# Copyright 2023 ETH Zurich and University of Bologna.
# Solderpad Hardware License, Version 0.51, see LICENSE for details.
# SPDX-License-Identifier: SHL-0.51

# LEF for the sg13g2_iocell library
# Automatically generated by gds2lef_sg13g2.py
# Extracted from sg13g2_iocell.gds

# Authors:
# - Thomas Benz <tbenz@iis.ee.ethz.ch>

VERSION 5.7 ;
BUSBITCHARS "<>" ;
DIVIDERCHAR "/" ;

PROPERTYDEFINITIONS
  MACRO CatenaDesignType STRING ;
END PROPERTYDEFINITIONS

SITE  IOSite
  CLASS    PAD ;
  SYMMETRY R90 ;
  SIZE	1.00 BY 310.00 ;
END  IOSite

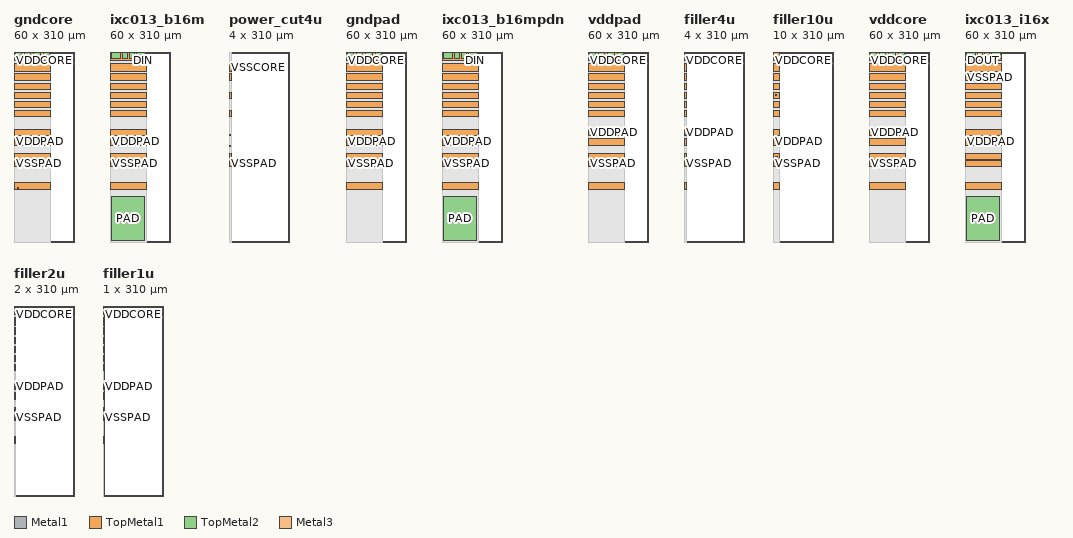
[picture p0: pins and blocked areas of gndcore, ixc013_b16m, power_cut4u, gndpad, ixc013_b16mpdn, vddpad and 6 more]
MACRO gndcore
  CLASS PAD ;
  ORIGIN 0 0 ;
  FOREIGN gndcore 0 0 ;
  SIZE 60 BY 310 ;
  SYMMETRY X Y R90 ;
  SITE IOSite ;
  PIN VSSPAD
    DIRECTION INOUT ;
    USE GROUND ;
    PORT
      LAYER Metal1 ;
        RECT 5.77 87.69 7.6 88.64 ;
    END
    PORT
      LAYER TopMetal1 ;
        RECT 0.0 122.745 60.0 132.745 ;
        RECT 0.0 134.39 60.0 144.39 ;
        RECT 0.0 204.15 60.0 214.15 ;
        RECT 0.0 234.15 60.0 244.15 ;
        RECT 0.0 264.15 60.0 274.15 ;
    END
  END VSSPAD
  PIN VDDPAD
    DIRECTION INOUT ;
    USE POWER ;
    PORT
      LAYER TopMetal1 ;
        RECT 0.0 86.405 60.0 96.405 ;
        RECT 0.0 219.15 60.0 229.15 ;
        RECT 0.0 249.15 60.0 259.15 ;
        RECT 0.0 158.15 60.0 168.65 ;
        RECT 0.0 173.65 60.0 184.15 ;
    END
  END VDDPAD
  PIN VDDCORE
    DIRECTION INOUT ;
    USE POWER ;
    PORT
      LAYER TopMetal1 ;
        RECT 0.0 296.15 60.0 309.15 ;
    END
    PORT
      LAYER TopMetal2 ;
        RECT 47.5 301.39 57.5 310.0 ;
        RECT 2.5 301.39 12.5 310.0 ;
    END
  END VDDCORE
  PIN VSSCORE
    DIRECTION INOUT ;
    USE GROUND ;
    PORT
      LAYER TopMetal1 ;
        RECT 0.0 278.15 60.0 291.15 ;
    END
    PORT
      LAYER TopMetal2 ;
        RECT 32.5 301.39 42.5 310.0 ;
        RECT 17.5 301.39 27.5 310.0 ;
    END
  END VSSCORE
  OBS
    LAYER Metal1 ;
      RECT 0 0 60 310 ;
    LAYER Metal2 ;
      RECT 0 0 60 310 ;
    LAYER Metal3 ;
      RECT 0 0 60 310 ;
    LAYER Metal4 ;
      RECT 0 0 60 310 ;
    LAYER Metal5 ;
      RECT 0 0 60 310 ;
    LAYER TopMetal1 ;
      RECT 0 0 60 310 ;
    LAYER TopMetal2 ;
      RECT 0 0 60 310 ;
  END
END gndcore

MACRO ixc013_b16m
  CLASS PAD ;
  ORIGIN 0 0 ;
  FOREIGN ixc013_b16m 0 0 ;
  SIZE 60 BY 310 ;
  SYMMETRY X Y R90 ;
  SITE IOSite ;
  PIN DOUT
    DIRECTION OUTPUT ;
    USE SIGNAL ;
    PORT
      LAYER Metal3 ;
        RECT 7.865 309.0 8.865 310.0 ;
    END
  END DOUT
  PIN OEN
    DIRECTION INPUT ;
    USE SIGNAL ;
    PORT
      LAYER Metal3 ;
        RECT 54.745 309.0 55.745 310.0 ;
    END
  END OEN
  PIN DIN
    DIRECTION INPUT ;
    USE SIGNAL ;
    PORT
      LAYER Metal3 ;
        RECT 52.745 309.0 53.745 310.0 ;
    END
  END DIN
  PIN VDDPAD
    DIRECTION INOUT ;
    USE POWER ;
    PORT
      LAYER TopMetal1 ;
        RECT 0.0 86.405 60.0 96.405 ;
        RECT 0.0 219.15 60.0 229.15 ;
        RECT 0.0 249.15 60.0 259.15 ;
        RECT 0.0 158.15 60.0 168.65 ;
        RECT 0.0 173.65 60.0 184.15 ;
    END
    PORT
      LAYER TopMetal2 ;
        RECT 1.96 298.75 16.96 310.0 ;
        RECT 32.085 298.75 40.085 310.0 ;
    END
  END VDDPAD
  PIN VSSPAD
    DIRECTION INOUT ;
    USE GROUND ;
    PORT
      LAYER TopMetal1 ;
        RECT 0.0 122.745 60.0 132.745 ;
        RECT 0.0 134.39 60.0 144.39 ;
        RECT 0.0 204.15 60.0 214.15 ;
        RECT 0.0 234.15 60.0 244.15 ;
        RECT 0.0 264.15 60.0 274.15 ;
    END
    PORT
      LAYER TopMetal2 ;
        RECT 20.085 298.75 28.085 310.0 ;
        RECT 43.21 298.75 58.21 310.0 ;
    END
  END VSSPAD
  PIN VDDCORE
    DIRECTION INOUT ;
    USE POWER ;
    PORT
      LAYER TopMetal1 ;
        RECT 0.0 296.15 60.0 309.15 ;
    END
  END VDDCORE
  PIN VSSCORE
    DIRECTION INOUT ;
    USE GROUND ;
    PORT
      LAYER TopMetal1 ;
        RECT 0.0 278.15 60.0 291.15 ;
    END
  END VSSCORE
  PIN PAD
    DIRECTION INOUT ;
    USE SIGNAL ;
    PORT
      LAYER TopMetal2 ;
        RECT 2.9 2.535 57.1 73.735 ;
    END
  END PAD
  OBS
    LAYER Metal1 ;
      RECT 0 0 60 310 ;
    LAYER Metal2 ;
      RECT 0 0 60 310 ;
    LAYER Metal3 ;
      RECT 0 0 60 310 ;
    LAYER Metal4 ;
      RECT 0 0 60 310 ;
    LAYER Metal5 ;
      RECT 0 0 60 310 ;
    LAYER TopMetal1 ;
      RECT 0 0 60 310 ;
    LAYER TopMetal2 ;
      RECT 0 0 60 310 ;
  END
END ixc013_b16m

MACRO power_cut4u
  CLASS PAD ;
  ORIGIN 0 0 ;
  FOREIGN power_cut4u 0 0 ;
  SIZE 4 BY 310 ;
  SYMMETRY X Y R90 ;
  SITE IOSite ;
  PIN VSSPAD
    DIRECTION INOUT ;
    USE GROUND ;
    PORT
      LAYER Metal1 ;
        RECT 1.42 173.42 2.58 174.59 ;
        RECT 1.28 155.28 2.72 157.2 ;
    END
    PORT
      LAYER TopMetal1 ;
        RECT 0.0 122.745 4.0 132.745 ;
        RECT 0.0 134.39 4.0 144.39 ;
        RECT 0.0 204.15 4.0 214.15 ;
        RECT 0.0 234.15 4.0 244.15 ;
        RECT 0.0 264.15 4.0 274.15 ;
    END
  END VSSPAD
  PIN VSSCORE
    DIRECTION INOUT ;
    USE GROUND ;
    PORT
      LAYER TopMetal1 ;
        RECT 0.0 278.15 4.0 291.15 ;
    END
  END VSSCORE
  OBS
    LAYER Metal1 ;
      RECT 0 0 4 310 ;
    LAYER Metal2 ;
      RECT 0 0 4 310 ;
    LAYER Metal3 ;
      RECT 0 0 4 310 ;
    LAYER Metal4 ;
      RECT 0 0 4 310 ;
    LAYER Metal5 ;
      RECT 0 0 4 310 ;
    LAYER TopMetal1 ;
      RECT 0 0 4 310 ;
    LAYER TopMetal2 ;
      RECT 0 0 4 310 ;
  END
END power_cut4u

MACRO gndpad
  CLASS PAD ;
  ORIGIN 0 0 ;
  FOREIGN gndpad 0 0 ;
  SIZE 60 BY 310 ;
  SYMMETRY X Y R90 ;
  SITE IOSite ;
  PIN VDDPAD
    DIRECTION INOUT ;
    USE POWER ;
    PORT
      LAYER TopMetal1 ;
        RECT 0.0 86.405 60.0 96.405 ;
        RECT 0.0 219.15 60.0 229.15 ;
        RECT 0.0 249.15 60.0 259.15 ;
        RECT 0.0 158.15 60.0 168.65 ;
        RECT 0.0 173.65 60.0 184.15 ;
    END
    PORT
      LAYER TopMetal2 ;
        RECT 47.5 301.39 57.5 310.0 ;
        RECT 2.5 301.39 12.5 310.0 ;
    END
  END VDDPAD
  PIN VSSPAD
    DIRECTION INOUT ;
    USE GROUND ;
    PORT
      LAYER TopMetal1 ;
        RECT 0.0 122.745 60.0 132.745 ;
        RECT 0.0 134.39 60.0 144.39 ;
        RECT 0.0 204.15 60.0 214.15 ;
        RECT 0.0 234.15 60.0 244.15 ;
        RECT 0.0 264.15 60.0 274.15 ;
    END
    PORT
      LAYER TopMetal2 ;
        RECT 32.5 301.39 42.5 310.0 ;
        RECT 17.5 301.39 27.5 310.0 ;
    END
  END VSSPAD
  PIN VDDCORE
    DIRECTION INOUT ;
    USE POWER ;
    PORT
      LAYER TopMetal1 ;
        RECT 0.0 296.15 60.0 309.15 ;
    END
  END VDDCORE
  PIN VSSCORE
    DIRECTION INOUT ;
    USE GROUND ;
    PORT
      LAYER TopMetal1 ;
        RECT 0.0 278.15 60.0 291.15 ;
    END
  END VSSCORE
  OBS
    LAYER Metal1 ;
      RECT 0 0 60 310 ;
    LAYER Metal2 ;
      RECT 0 0 60 310 ;
    LAYER Metal3 ;
      RECT 0 0 60 310 ;
    LAYER Metal4 ;
      RECT 0 0 60 310 ;
    LAYER Metal5 ;
      RECT 0 0 60 310 ;
    LAYER TopMetal1 ;
      RECT 0 0 60 310 ;
    LAYER TopMetal2 ;
      RECT 0 0 60 310 ;
  END
END gndpad

MACRO ixc013_b16mpdn
  CLASS PAD ;
  ORIGIN 0 0 ;
  FOREIGN ixc013_b16mpdn 0 0 ;
  SIZE 60 BY 310 ;
  SYMMETRY X Y R90 ;
  SITE IOSite ;
  PIN DOUT
    DIRECTION OUTPUT ;
    USE SIGNAL ;
    PORT
      LAYER Metal3 ;
        RECT 7.865 309.0 8.865 310.0 ;
    END
  END DOUT
  PIN OEN
    DIRECTION INPUT ;
    USE SIGNAL ;
    PORT
      LAYER Metal3 ;
        RECT 54.745 309.0 55.745 310.0 ;
    END
  END OEN
  PIN DIN
    DIRECTION INPUT ;
    USE SIGNAL ;
    PORT
      LAYER Metal3 ;
        RECT 52.745 309.0 53.745 310.0 ;
    END
  END DIN
  PIN VDDPAD
    DIRECTION INOUT ;
    USE POWER ;
    PORT
      LAYER TopMetal1 ;
        RECT 0.0 86.405 60.0 96.405 ;
        RECT 0.0 219.15 60.0 229.15 ;
        RECT 0.0 249.15 60.0 259.15 ;
        RECT 0.0 158.15 60.0 168.65 ;
        RECT 0.0 173.65 60.0 184.15 ;
    END
    PORT
      LAYER TopMetal2 ;
        RECT 1.96 298.75 16.96 310.0 ;
        RECT 32.085 298.75 40.085 310.0 ;
    END
  END VDDPAD
  PIN VSSPAD
    DIRECTION INOUT ;
    USE GROUND ;
    PORT
      LAYER TopMetal1 ;
        RECT 0.0 122.745 60.0 132.745 ;
        RECT 0.0 134.39 60.0 144.39 ;
        RECT 0.0 204.15 60.0 214.15 ;
        RECT 0.0 234.15 60.0 244.15 ;
        RECT 0.0 264.15 60.0 274.15 ;
    END
    PORT
      LAYER TopMetal2 ;
        RECT 20.085 298.75 28.085 310.0 ;
        RECT 43.21 298.75 58.21 310.0 ;
    END
  END VSSPAD
  PIN VDDCORE
    DIRECTION INOUT ;
    USE POWER ;
    PORT
      LAYER TopMetal1 ;
        RECT 0.0 296.15 60.0 309.15 ;
    END
  END VDDCORE
  PIN VSSCORE
    DIRECTION INOUT ;
    USE GROUND ;
    PORT
      LAYER TopMetal1 ;
        RECT 0.0 278.15 60.0 291.15 ;
    END
  END VSSCORE
  PIN PAD
    DIRECTION INOUT ;
    USE SIGNAL ;
    PORT
      LAYER TopMetal2 ;
        RECT 2.9 2.535 57.1 73.735 ;
    END
  END PAD
  OBS
    LAYER Metal1 ;
      RECT 0 0 60 310 ;
    LAYER Metal2 ;
      RECT 0 0 60 310 ;
    LAYER Metal3 ;
      RECT 0 0 60 310 ;
    LAYER Metal4 ;
      RECT 0 0 60 310 ;
    LAYER Metal5 ;
      RECT 0 0 60 310 ;
    LAYER TopMetal1 ;
      RECT 0 0 60 310 ;
    LAYER TopMetal2 ;
      RECT 0 0 60 310 ;
  END
END ixc013_b16mpdn

MACRO vddpad
  CLASS PAD ;
  ORIGIN 0 0 ;
  FOREIGN vddpad 0 0 ;
  SIZE 60 BY 310 ;
  SYMMETRY X Y R90 ;
  SITE IOSite ;
  PIN VDDPAD
    DIRECTION INOUT ;
    USE POWER ;
    PORT
      LAYER TopMetal1 ;
        RECT 0.0 86.405 60.0 96.405 ;
        RECT 0.0 219.15 60.0 229.15 ;
        RECT 0.0 249.15 60.0 259.15 ;
        RECT 0.0 173.65 60.0 184.15 ;
        RECT 0.0 158.15 60.0 168.65 ;
    END
    PORT
      LAYER TopMetal2 ;
        RECT 17.5 301.39 27.5 310.0 ;
        RECT 32.5 301.39 42.5 310.0 ;
    END
  END VDDPAD
  PIN VSSPAD
    DIRECTION INOUT ;
    USE GROUND ;
    PORT
      LAYER TopMetal1 ;
        RECT 0.0 122.745 60.0 132.745 ;
        RECT 0.0 134.39 60.0 144.39 ;
        RECT 0.0 204.15 60.0 214.15 ;
        RECT 0.0 234.15 60.0 244.15 ;
        RECT 0.0 264.15 60.0 274.15 ;
    END
    PORT
      LAYER TopMetal2 ;
        RECT 47.5 301.39 57.5 310.0 ;
        RECT 2.5 301.39 12.5 310.0 ;
    END
  END VSSPAD
  PIN VSSCORE
    DIRECTION INOUT ;
    USE GROUND ;
    PORT
      LAYER TopMetal1 ;
        RECT 0.0 278.15 60.0 291.15 ;
    END
  END VSSCORE
  PIN VDDCORE
    DIRECTION INOUT ;
    USE POWER ;
    PORT
      LAYER TopMetal1 ;
        RECT 0.0 296.15 60.0 309.15 ;
    END
  END VDDCORE
  OBS
    LAYER Metal1 ;
      RECT 0 0 60 310 ;
    LAYER Metal2 ;
      RECT 0 0 60 310 ;
    LAYER Metal3 ;
      RECT 0 0 60 310 ;
    LAYER Metal4 ;
      RECT 0 0 60 310 ;
    LAYER Metal5 ;
      RECT 0 0 60 310 ;
    LAYER TopMetal1 ;
      RECT 0 0 60 310 ;
    LAYER TopMetal2 ;
      RECT 0 0 60 310 ;
  END
END vddpad

MACRO filler4u
  CLASS PAD SPACER ;
  ORIGIN 0 0 ;
  FOREIGN filler4u 0 0 ;
  SIZE 4 BY 310 ;
  SYMMETRY X Y R90 ;
  SITE IOSite ;
  PIN VSSPAD
    DIRECTION INOUT ;
    USE GROUND ;
    PORT
      LAYER Metal1 ;
        RECT 1.42 156.98 2.4 157.67 ;
        RECT 1.5 174.18 2.28 175.11 ;
    END
    PORT
      LAYER TopMetal1 ;
        RECT 0.0 122.745 4.0 132.745 ;
        RECT 0.0 134.39 4.0 144.39 ;
        RECT 0.0 204.15 4.0 214.15 ;
        RECT 0.0 234.15 4.0 244.15 ;
        RECT 0.0 264.15 4.0 274.15 ;
    END
  END VSSPAD
  PIN VDDCORE
    DIRECTION INOUT ;
    USE POWER ;
    PORT
      LAYER Metal1 ;
        RECT 0.0 307.0 4.0 310.0 ;
    END
    PORT
      LAYER TopMetal1 ;
        RECT 0.0 296.15 4.0 309.15 ;
    END
  END VDDCORE
  PIN VDDPAD
    DIRECTION INOUT ;
    USE POWER ;
    PORT
      LAYER TopMetal1 ;
        RECT 0.0 86.405 4.0 96.405 ;
        RECT 0.0 219.15 4.0 229.15 ;
        RECT 0.0 249.15 4.0 259.15 ;
        RECT 0.0 173.65 4.0 184.15 ;
        RECT 0.0 158.15 4.0 168.65 ;
    END
  END VDDPAD
  PIN VSSCORE
    DIRECTION INOUT ;
    USE GROUND ;
    PORT
      LAYER TopMetal1 ;
        RECT 0.0 278.15 4.0 291.15 ;
    END
  END VSSCORE
  OBS
    LAYER Metal1 ;
      RECT 0 0 4 310 ;
    LAYER Metal2 ;
      RECT 0 0 4 310 ;
    LAYER Metal3 ;
      RECT 0 0 4 310 ;
    LAYER Metal4 ;
      RECT 0 0 4 310 ;
    LAYER Metal5 ;
      RECT 0 0 4 310 ;
    LAYER TopMetal1 ;
      RECT 0 0 4 310 ;
    LAYER TopMetal2 ;
      RECT 0 0 4 310 ;
  END
END filler4u

MACRO filler10u
  CLASS PAD SPACER ;
  ORIGIN 0 0 ;
  FOREIGN filler10u 0 0 ;
  SIZE 10 BY 310 ;
  SYMMETRY X Y R90 ;
  SITE IOSite ;
  PIN VSSPAD
    DIRECTION INOUT ;
    USE GROUND ;
    PORT
      LAYER Metal1 ;
        RECT 3.89 137.25 6.75 139.37 ;
        RECT 3.55 238.53 6.06 240.52 ;
    END
    PORT
      LAYER TopMetal1 ;
        RECT 0.0 122.745 10.0 132.745 ;
        RECT 0.0 134.39 10.0 144.39 ;
        RECT 0.0 204.15 10.0 214.15 ;
        RECT 0.0 234.15 10.0 244.15 ;
        RECT 0.0 264.15 10.0 274.15 ;
    END
  END VSSPAD
  PIN VDDPAD
    DIRECTION INOUT ;
    USE POWER ;
    PORT
      LAYER TopMetal1 ;
        RECT 0.0 219.15 10.0 229.15 ;
        RECT 0.0 249.15 10.0 259.15 ;
        RECT 0.0 158.15 10.0 168.65 ;
        RECT 0.0 86.405 10.0 96.405 ;
        RECT 0.0 173.65 10.0 184.15 ;
    END
  END VDDPAD
  PIN VDDCORE
    DIRECTION INOUT ;
    USE POWER ;
    PORT
      LAYER TopMetal1 ;
        RECT 0.0 296.15 10.0 309.15 ;
    END
  END VDDCORE
  PIN VSSCORE
    DIRECTION INOUT ;
    USE GROUND ;
    PORT
      LAYER TopMetal1 ;
        RECT 0.0 278.15 10.0 291.15 ;
    END
  END VSSCORE
  OBS
    LAYER Metal1 ;
      RECT 0 0 10 310 ;
    LAYER Metal2 ;
      RECT 0 0 10 310 ;
    LAYER Metal3 ;
      RECT 0 0 10 310 ;
    LAYER Metal4 ;
      RECT 0 0 10 310 ;
    LAYER Metal5 ;
      RECT 0 0 10 310 ;
    LAYER TopMetal1 ;
      RECT 0 0 10 310 ;
    LAYER TopMetal2 ;
      RECT 0 0 10 310 ;
  END
END filler10u

MACRO vddcore
  CLASS PAD ;
  ORIGIN 0 0 ;
  FOREIGN vddcore 0 0 ;
  SIZE 60 BY 310 ;
  SYMMETRY X Y R90 ;
  SITE IOSite ;
  PIN VDDPAD
    DIRECTION INOUT ;
    USE POWER ;
    PORT
      LAYER TopMetal1 ;
        RECT 0.0 173.65 60.0 184.15 ;
        RECT 0.0 86.405 60.0 96.405 ;
        RECT 0.0 219.15 60.0 229.15 ;
        RECT 0.0 249.15 60.0 259.15 ;
        RECT 0.0 158.15 60.0 168.65 ;
    END
  END VDDPAD
  PIN VSSPAD
    DIRECTION INOUT ;
    USE GROUND ;
    PORT
      LAYER TopMetal1 ;
        RECT 0.0 122.745 60.0 132.745 ;
        RECT 0.0 134.39 60.0 144.39 ;
        RECT 0.0 204.15 60.0 214.15 ;
        RECT 0.0 234.15 60.0 244.15 ;
        RECT 0.0 264.15 60.0 274.15 ;
    END
  END VSSPAD
  PIN VDDCORE
    DIRECTION INOUT ;
    USE POWER ;
    PORT
      LAYER TopMetal1 ;
        RECT 0.0 296.15 60.0 309.15 ;
    END
    PORT
      LAYER TopMetal2 ;
        RECT 32.5 301.39 42.5 310.0 ;
        RECT 17.5 301.39 27.5 310.0 ;
    END
  END VDDCORE
  PIN VSSCORE
    DIRECTION INOUT ;
    USE GROUND ;
    PORT
      LAYER TopMetal1 ;
        RECT 0.0 278.15 60.0 291.15 ;
    END
    PORT
      LAYER TopMetal2 ;
        RECT 2.5 301.39 12.5 310.0 ;
        RECT 47.5 301.39 57.5 310.0 ;
    END
  END VSSCORE
  OBS
    LAYER Metal1 ;
      RECT 0 0 60 310 ;
    LAYER Metal2 ;
      RECT 0 0 60 310 ;
    LAYER Metal3 ;
      RECT 0 0 60 310 ;
    LAYER Metal4 ;
      RECT 0 0 60 310 ;
    LAYER Metal5 ;
      RECT 0 0 60 310 ;
    LAYER TopMetal1 ;
      RECT 0 0 60 310 ;
    LAYER TopMetal2 ;
      RECT 0 0 60 310 ;
  END
END vddcore

MACRO ixc013_i16x
  CLASS PAD ;
  ORIGIN 0 0 ;
  FOREIGN ixc013_i16x 0 0 ;
  SIZE 60 BY 310 ;
  SYMMETRY X Y R90 ;
  SITE IOSite ;
  PIN DOUT
    DIRECTION OUTPUT ;
    USE SIGNAL ;
    PORT
      LAYER Metal3 ;
        RECT 7.865 309.0 8.865 310.0 ;
    END
  END DOUT
  PIN VSSPAD
    DIRECTION INOUT ;
    USE GROUND ;
    PORT
      LAYER TopMetal1 ;
        RECT 0.0 264.15 60.0 274.15 ;
        RECT 0.0 234.15 60.0 244.15 ;
        RECT 0.0 204.15 60.0 214.15 ;
        RECT 0.0 134.39 60.0 144.39 ;
        RECT 0.0 122.745 60.0 132.745 ;
    END
    PORT
      LAYER TopMetal2 ;
        RECT 20.085 298.75 28.085 310.0 ;
        RECT 43.21 298.75 58.21 310.0 ;
    END
  END VSSPAD
  PIN VDDPAD
    DIRECTION INOUT ;
    USE POWER ;
    PORT
      LAYER TopMetal1 ;
        RECT 0.0 249.15 60.0 259.15 ;
        RECT 0.0 219.15 60.0 229.15 ;
        RECT 0.0 86.405 60.0 96.405 ;
        RECT 0.0 158.15 60.0 168.65 ;
        RECT 0.0 173.65 60.0 184.15 ;
    END
    PORT
      LAYER TopMetal2 ;
        RECT 32.085 298.75 40.085 310.0 ;
        RECT 1.96 298.75 16.96 310.0 ;
    END
  END VDDPAD
  PIN VSSCORE
    DIRECTION INOUT ;
    USE GROUND ;
    PORT
      LAYER TopMetal1 ;
        RECT 0.0 278.15 60.0 291.15 ;
    END
  END VSSCORE
  PIN VDDCORE
    DIRECTION INOUT ;
    USE POWER ;
    PORT
      LAYER TopMetal1 ;
        RECT 0.0 296.15 60.0 309.15 ;
    END
  END VDDCORE
  PIN PAD
    DIRECTION INOUT ;
    USE SIGNAL ;
    PORT
      LAYER TopMetal2 ;
        RECT 2.9 2.535 57.1 73.735 ;
    END
  END PAD
  OBS
    LAYER Metal1 ;
      RECT 0 0 60 310 ;
    LAYER Metal2 ;
      RECT 0 0 60 310 ;
    LAYER Metal3 ;
      RECT 0 0 60 310 ;
    LAYER Metal4 ;
      RECT 0 0 60 310 ;
    LAYER Metal5 ;
      RECT 0 0 60 310 ;
    LAYER TopMetal1 ;
      RECT 0 0 60 310 ;
    LAYER TopMetal2 ;
      RECT 0 0 60 310 ;
  END
END ixc013_i16x

MACRO filler2u
  CLASS PAD SPACER ;
  ORIGIN 0 0 ;
  FOREIGN filler2u 0 0 ;
  SIZE 2 BY 310 ;
  SYMMETRY X Y R90 ;
  SITE IOSite ;
  PIN VSSPAD
    DIRECTION INOUT ;
    USE GROUND ;
    PORT
      LAYER Metal1 ;
        RECT 0.64 174.28 1.5 175.54 ;
        RECT 0.44 159.17 1.37 160.1 ;
    END
    PORT
      LAYER TopMetal1 ;
        RECT 0.0 122.745 2.0 132.745 ;
        RECT 0.0 134.39 2.0 144.39 ;
        RECT 0.0 204.15 2.0 214.15 ;
        RECT 0.0 234.15 2.0 244.15 ;
        RECT 0.0 264.15 2.0 274.15 ;
    END
  END VSSPAD
  PIN VDDCORE
    DIRECTION INOUT ;
    USE POWER ;
    PORT
      LAYER Metal1 ;
        RECT 0.0 307.0 2.0 310.0 ;
    END
    PORT
      LAYER TopMetal1 ;
        RECT 0.0 296.15 2.0 309.15 ;
    END
  END VDDCORE
  PIN VDDPAD
    DIRECTION INOUT ;
    USE POWER ;
    PORT
      LAYER TopMetal1 ;
        RECT 0.0 86.405 2.0 96.405 ;
        RECT 0.0 219.15 2.0 229.15 ;
        RECT 0.0 249.15 2.0 259.15 ;
        RECT 0.0 173.65 2.0 184.15 ;
        RECT 0.0 158.15 2.0 168.65 ;
    END
  END VDDPAD
  PIN VSSCORE
    DIRECTION INOUT ;
    USE GROUND ;
    PORT
      LAYER TopMetal1 ;
        RECT 0.0 278.15 2.0 291.15 ;
    END
  END VSSCORE
  OBS
    LAYER Metal1 ;
      RECT 0 0 2 310 ;
    LAYER Metal2 ;
      RECT 0 0 2 310 ;
    LAYER Metal3 ;
      RECT 0 0 2 310 ;
    LAYER Metal4 ;
      RECT 0 0 2 310 ;
    LAYER Metal5 ;
      RECT 0 0 2 310 ;
    LAYER TopMetal1 ;
      RECT 0 0 2 310 ;
    LAYER TopMetal2 ;
      RECT 0 0 2 310 ;
  END
END filler2u

MACRO filler1u
  CLASS PAD SPACER ;
  ORIGIN 0 0 ;
  FOREIGN filler1u 0 0 ;
  SIZE 1 BY 310 ;
  SYMMETRY X Y R90 ;
  SITE IOSite ;
  PIN VSSPAD
    DIRECTION INOUT ;
    USE GROUND ;
    PORT
      LAYER Metal1 ;
        RECT 0.13 178.87 0.86 179.26 ;
        RECT 0.23 111.51 0.73 112.4 ;
    END
    PORT
      LAYER TopMetal1 ;
        RECT 0.0 122.745 1.0 132.745 ;
        RECT 0.0 134.39 1.0 144.39 ;
        RECT 0.0 204.15 1.0 214.15 ;
        RECT 0.0 234.15 1.0 244.15 ;
        RECT 0.0 264.15 1.0 274.15 ;
    END
  END VSSPAD
  PIN VDDPAD
    DIRECTION INOUT ;
    USE POWER ;
    PORT
      LAYER TopMetal1 ;
        RECT 0.0 86.405 1.0 96.405 ;
        RECT 0.0 219.15 1.0 229.15 ;
        RECT 0.0 249.15 1.0 259.15 ;
        RECT 0.0 173.65 1.0 184.15 ;
        RECT 0.0 158.15 1.0 168.65 ;
    END
  END VDDPAD
  PIN VDDCORE
    DIRECTION INOUT ;
    USE POWER ;
    PORT
      LAYER TopMetal1 ;
        RECT 0.0 296.15 1.0 309.15 ;
    END
  END VDDCORE
  PIN VSSCORE
    DIRECTION INOUT ;
    USE GROUND ;
    PORT
      LAYER TopMetal1 ;
        RECT 0.0 278.15 1.0 291.15 ;
    END
  END VSSCORE
  OBS
    LAYER Metal1 ;
      RECT 0 0 1 310 ;
    LAYER Metal2 ;
      RECT 0 0 1 310 ;
    LAYER Metal3 ;
      RECT 0 0 1 310 ;
    LAYER Metal4 ;
      RECT 0 0 1 310 ;
    LAYER Metal5 ;
      RECT 0 0 1 310 ;
    LAYER TopMetal1 ;
      RECT 0 0 1 310 ;
    LAYER TopMetal2 ;
      RECT 0 0 1 310 ;
  END
END filler1u

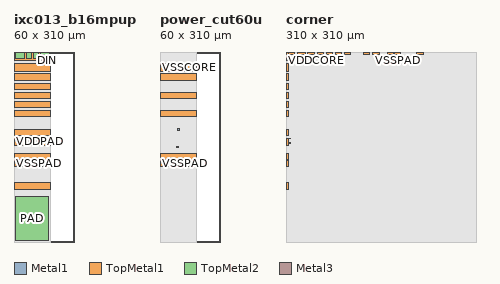
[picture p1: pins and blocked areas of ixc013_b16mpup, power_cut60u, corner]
MACRO ixc013_b16mpup
  CLASS PAD ;
  ORIGIN 0 0 ;
  FOREIGN ixc013_b16mpup 0 0 ;
  SIZE 60 BY 310 ;
  SYMMETRY X Y R90 ;
  SITE IOSite ;
  PIN DOUT
    DIRECTION OUTPUT ;
    USE SIGNAL ;
    PORT
      LAYER Metal3 ;
        RECT 7.865 309.0 8.865 310.0 ;
    END
  END DOUT
  PIN DIN
    DIRECTION INPUT ;
    USE SIGNAL ;
    PORT
      LAYER Metal3 ;
        RECT 52.745 309.0 53.745 310.0 ;
    END
  END DIN
  PIN OEN
    DIRECTION INPUT ;
    USE SIGNAL ;
    PORT
      LAYER Metal3 ;
        RECT 54.745 309.0 55.745 310.0 ;
        RECT 54.745 309.0 55.745 310.0 ;
    END
  END OEN
  PIN VDDPAD
    DIRECTION INOUT ;
    USE POWER ;
    PORT
      LAYER TopMetal1 ;
        RECT 0.0 86.405 60.0 96.405 ;
        RECT 0.0 219.15 60.0 229.15 ;
        RECT 0.0 249.15 60.0 259.15 ;
        RECT 0.0 158.15 60.0 168.65 ;
        RECT 0.0 173.65 60.0 184.15 ;
    END
    PORT
      LAYER TopMetal2 ;
        RECT 1.96 298.75 16.96 310.0 ;
        RECT 32.085 298.75 40.085 310.0 ;
    END
  END VDDPAD
  PIN VSSPAD
    DIRECTION INOUT ;
    USE GROUND ;
    PORT
      LAYER TopMetal1 ;
        RECT 0.0 122.745 60.0 132.745 ;
        RECT 0.0 134.39 60.0 144.39 ;
        RECT 0.0 204.15 60.0 214.15 ;
        RECT 0.0 234.15 60.0 244.15 ;
        RECT 0.0 264.15 60.0 274.15 ;
    END
    PORT
      LAYER TopMetal2 ;
        RECT 20.085 298.75 28.085 310.0 ;
        RECT 43.21 298.75 58.21 310.0 ;
    END
  END VSSPAD
  PIN VDDCORE
    DIRECTION INOUT ;
    USE POWER ;
    PORT
      LAYER TopMetal1 ;
        RECT 0.0 296.15 60.0 309.15 ;
    END
  END VDDCORE
  PIN VSSCORE
    DIRECTION INOUT ;
    USE GROUND ;
    PORT
      LAYER TopMetal1 ;
        RECT 0.0 278.15 60.0 291.15 ;
    END
  END VSSCORE
  PIN PAD
    DIRECTION INOUT ;
    USE SIGNAL ;
    PORT
      LAYER TopMetal2 ;
        RECT 2.9 2.535 57.1 73.735 ;
    END
  END PAD
  OBS
    LAYER Metal1 ;
      RECT 0 0 60 310 ;
    LAYER Metal2 ;
      RECT 0 0 60 310 ;
    LAYER Metal3 ;
      RECT 0 0 60 310 ;
    LAYER Metal4 ;
      RECT 0 0 60 310 ;
    LAYER Metal5 ;
      RECT 0 0 60 310 ;
    LAYER TopMetal1 ;
      RECT 0 0 60 310 ;
    LAYER TopMetal2 ;
      RECT 0 0 60 310 ;
  END
END ixc013_b16mpup

MACRO power_cut60u
  CLASS PAD ;
  ORIGIN 0 0 ;
  FOREIGN power_cut60u 0 0 ;
  SIZE 60 BY 310 ;
  SYMMETRY X Y R90 ;
  SITE IOSite ;
  PIN VSSPAD
    DIRECTION INOUT ;
    USE GROUND ;
    PORT
      LAYER Metal1 ;
        RECT 26.89 154.13 29.44 155.41 ;
        RECT 28.88 181.55 32.43 185.11 ;
    END
    PORT
      LAYER TopMetal1 ;
        RECT 0.0 122.745 60.0 132.745 ;
        RECT 0.0 134.39 60.0 144.39 ;
        RECT 0.0 204.15 60.0 214.15 ;
        RECT 0.0 234.15 60.0 244.15 ;
        RECT 0.0 264.15 60.0 274.15 ;
    END
  END VSSPAD
  PIN VSSCORE
    DIRECTION INOUT ;
    USE GROUND ;
    PORT
      LAYER TopMetal1 ;
        RECT 0.0 278.15 60.0 291.15 ;
    END
  END VSSCORE
  OBS
    LAYER Metal1 ;
      RECT 0 0 60 310 ;
    LAYER Metal2 ;
      RECT 0 0 60 310 ;
    LAYER Metal3 ;
      RECT 0 0 60 310 ;
    LAYER Metal4 ;
      RECT 0 0 60 310 ;
    LAYER Metal5 ;
      RECT 0 0 60 310 ;
    LAYER TopMetal1 ;
      RECT 0 0 60 310 ;
    LAYER TopMetal2 ;
      RECT 0 0 60 310 ;
  END
END power_cut60u

MACRO corner
  CLASS PAD ;
  ORIGIN 0 0 ;
  FOREIGN corner 0 0 ;
  SIZE 310 BY 310 ;
  SYMMETRY X Y R90 ;
  SITE IOSite ;
  PIN VSSPAD
    DIRECTION INOUT ;
    USE GROUND ;
    PORT
      LAYER Metal1 ;
        RECT 4.08 161.48 7.25 162.45 ;
        RECT 4.89 168.25 6.61 169.11 ;
    END
    PORT
      LAYER TopMetal1 ;
        RECT 177.255 306.0 187.255 310.0 ;
        RECT 165.61 306.0 175.61 310.0 ;
        RECT 95.85 306.0 105.85 310.0 ;
        RECT 65.85 306.0 75.85 310.0 ;
        RECT 35.85 306.0 45.85 310.0 ;
        RECT 0.0 264.15 4.0 274.15 ;
        RECT 0.0 234.15 4.0 244.15 ;
        RECT 0.0 204.15 4.0 214.15 ;
        RECT 0.0 134.39 4.0 144.39 ;
        RECT 0.0 122.745 4.0 132.745 ;
    END
  END VSSPAD
  PIN VDDPAD
    DIRECTION INOUT ;
    USE POWER ;
    PORT
      LAYER TopMetal1 ;
        RECT 213.595 306.0 223.595 310.0 ;
        RECT 80.85 306.0 90.85 310.0 ;
        RECT 50.85 306.0 60.85 310.0 ;
        RECT 141.35 306.0 151.85 310.0 ;
        RECT 125.85 306.0 136.35 310.0 ;
        RECT 0.0 249.15 4.0 259.15 ;
        RECT 0.0 219.15 4.0 229.15 ;
        RECT 0.0 173.65 4.0 184.15 ;
        RECT 0.0 158.15 4.0 168.65 ;
        RECT 0.0 86.405 4.0 96.405 ;
    END
  END VDDPAD
  PIN VSSCORE
    DIRECTION INOUT ;
    USE GROUND ;
    PORT
      LAYER TopMetal1 ;
        RECT 18.85 306.0 31.85 310.0 ;
        RECT 0.0 278.15 4.0 291.15 ;
    END
  END VSSCORE
  PIN VDDCORE
    DIRECTION INOUT ;
    USE POWER ;
    PORT
      LAYER TopMetal1 ;
        RECT 0.85 306.0 13.85 310.0 ;
        RECT 0.0 296.15 4.0 309.15 ;
    END
  END VDDCORE
  OBS
    LAYER Metal1 ;
      RECT 0 0 310 310 ;
    LAYER Metal2 ;
      RECT 0 0 310 310 ;
    LAYER Metal3 ;
      RECT 0 0 310 310 ;
    LAYER Metal4 ;
      RECT 0 0 310 310 ;
    LAYER Metal5 ;
      RECT 0 0 310 310 ;
    LAYER TopMetal1 ;
      RECT 0 0 310 310 ;
    LAYER TopMetal2 ;
      RECT 0 0 310 310 ;
  END
END corner

